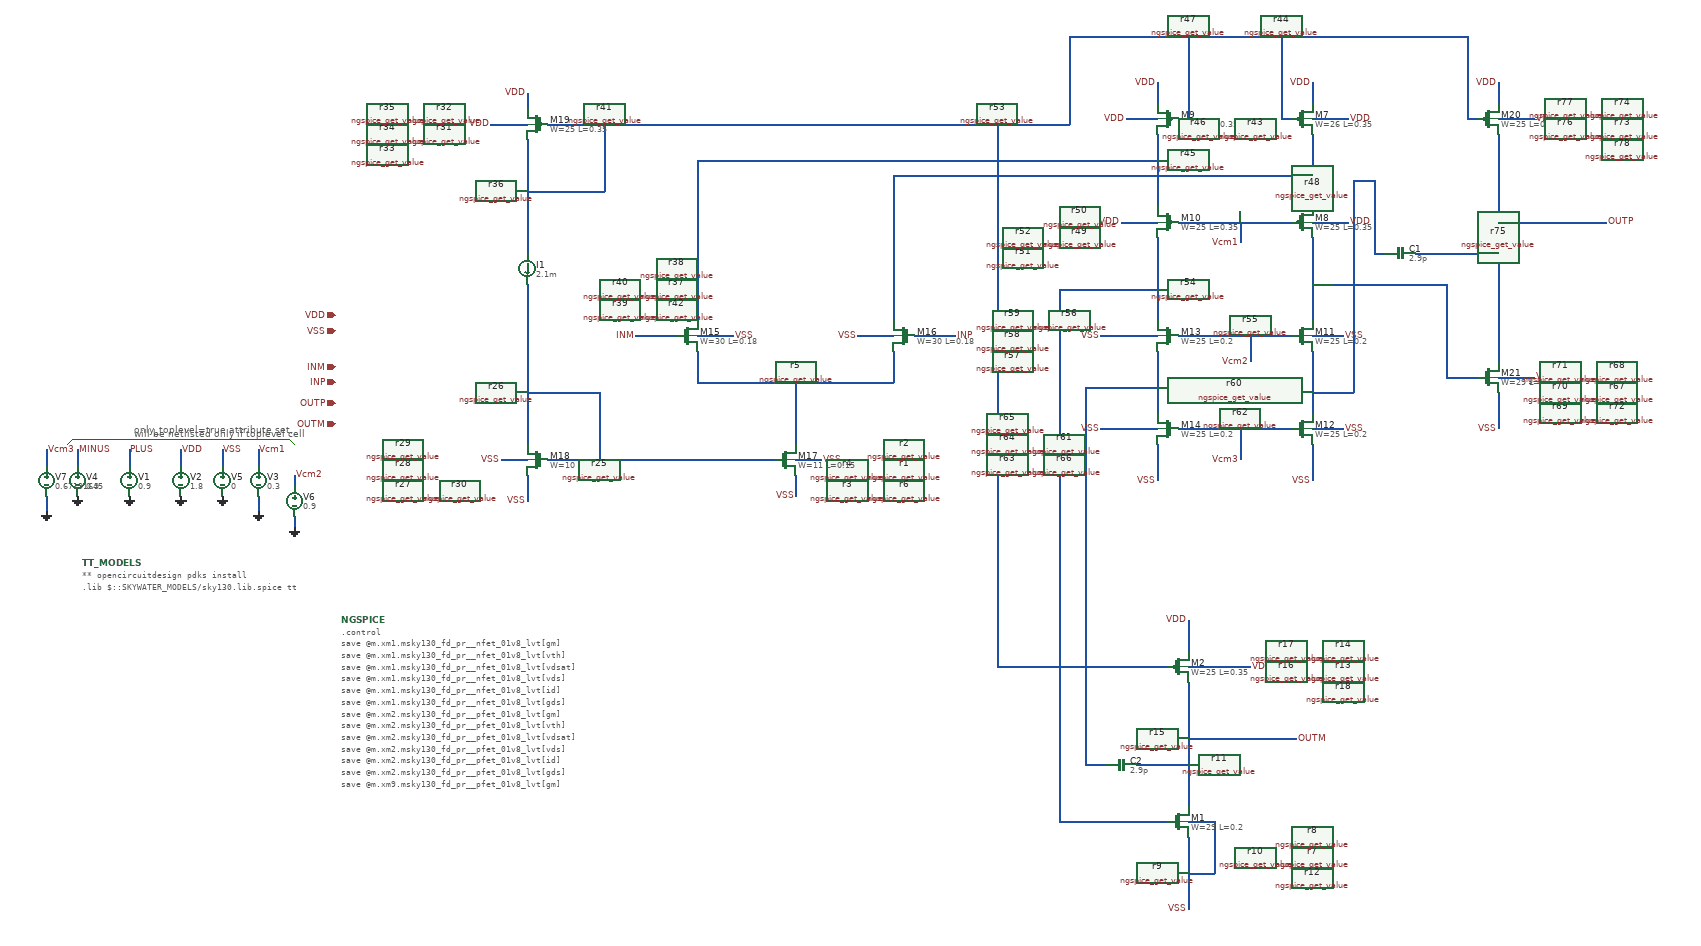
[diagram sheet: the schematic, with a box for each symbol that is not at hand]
v {xschem version=3.0.0 file_version=1.2 }
G {}
K {}
V {}
S {}
E {}
L 4 -460 -200 -90 -200 {}
L 4 -40 -200 -30 -190 {}
L 4 -470 -190 -460 -200 {}
L 4 -90 -200 -40 -200 {}
T {only_toplevel=true attribute set, 
will be netlisted only if toplevel cell} -340 -230 0 0 0.2 0.2 {layer=4}
N -350 -180 -350 -150 { lab=PLUS}
N -450 -180 -450 -150 { lab=MINUS}
N -170 -180 -170 -150 {
lab=VSS}
N -250 -180 -250 -150 {
lab=VDD}
N 1940 -790 1940 -650 {
lab=#net1}
N 1940 -590 1940 -430 {
lab=#net2}
N 1940 -370 1940 -250 {
lab=#net3}
N 1640 -790 1640 -650 {
lab=#net4}
N 1640 -590 1640 -430 {
lab=#net5}
N 1640 -370 1640 -250 {
lab=#net6}
N 750 -370 750 -310 {
lab=#net7}
N 750 -310 1130 -310 {
lab=#net7}
N 1130 -370 1130 -310 {
lab=#net7}
N 940 -310 940 -190 {
lab=#net7}
N 420 -500 420 -190 {
lab=#net8}
N 420 -780 420 -560 {
lab=#net9}
N 750 -740 750 -430 {
lab=#net4}
N 750 -740 1640 -740 {
lab=#net4}
N 1130 -710 1130 -430 {
lab=#net1}
N 1130 -710 1940 -710 {
lab=#net1}
N 1680 -220 1900 -220 {
lab=Vcm3}
N 1680 -400 1900 -400 {
lab=Vcm2}
N 1680 -620 1900 -620 {
lab=Vcm1}
N 2300 -790 2300 -350 {
lab=OUT}
N 2140 -560 2300 -560 {
lab=OUT}
N 2200 -320 2260 -320 {
lab=#net2}
N 2200 -500 2200 -320 {
lab=#net2}
N 1940 -500 2200 -500 {
lab=#net2}
N 460 -160 900 -160 {
lab=#net8}
N 460 -810 1470 -810 {
lab=#net9}
N 1470 -980 1470 -810 {
lab=#net9}
N 1680 -820 1700 -820 {
lab=#net9}
N 1700 -980 1700 -820 {
lab=#net9}
N 1880 -820 1900 -820 {
lab=#net9}
N 1880 -980 1880 -820 {
lab=#net9}
N 2240 -820 2260 -820 {
lab=#net9}
N 2240 -980 2240 -820 {
lab=#net9}
N 420 -130 420 -80 {
lab=VSS}
N 940 -130 940 -90 {
lab=VSS}
N 1640 -190 1640 -120 {
lab=VSS}
N 1940 -190 1940 -120 {
lab=VSS}
N 2300 -290 2300 -220 {
lab=VSS}
N 420 -870 420 -840 {
lab=VDD}
N 1940 -890 1940 -850 {
lab=VDD}
N 2300 -890 2300 -850 {
lab=VDD}
N 1530 -220 1640 -220 {
lab=VSS}
N 1530 -400 1640 -400 {
lab=VSS}
N 2300 -320 2370 -320 {
lab=VSS}
N 1940 -220 2000 -220 {
lab=VSS}
N 1940 -400 2000 -400 {
lab=VSS}
N 2300 -820 2370 -820 {
lab=VDD}
N 1940 -620 2010 -620 {
lab=VDD}
N 1940 -820 2010 -820 {
lab=VDD}
N 1580 -820 1640 -820 {
lab=VDD}
N 1570 -620 1640 -620 {
lab=VDD}
N 1640 -890 1640 -850 {
lab=VDD}
N 1060 -400 1130 -400 {
lab=VSS}
N 750 -400 820 -400 {
lab=VSS}
N 350 -810 420 -810 {
lab=VDD}
N 370 -160 420 -160 {
lab=VSS}
N 940 -160 990 -160 {
lab=VSS}
N 1470 -980 2240 -980 {
lab=#net9}
N 1170 -400 1250 -400 {
lab=PLUS}
N 630 -400 710 -400 {
lab=MINUS}
N 420 -680 570 -680 {
lab=#net9}
N 570 -810 570 -680 {
lab=#net9}
N 1800 -620 1800 -580 {
lab=Vcm1}
N 1820 -400 1820 -350 {
lab=Vcm2}
N 2300 -620 2510 -620 {
lab=OUT}
N -30 -130 -30 -110 {
lab=Vcm2}
N -100 -180 -100 -150 {
lab=Vcm1}
N -100 -90 -100 -60 {
lab=GND}
N -30 -50 -30 -30 {
lab=GND}
N 420 -290 560 -290 {
lab=#net8}
N 560 -290 560 -160 {
lab=#net8}
N 1800 -220 1800 -160 {
lab=Vcm3}
N 1450 -490 1640 -490 {
lab=#net5}
N 1450 -490 1450 140 {
lab=#net5}
N 1330 240 1660 240 {
lab=#net9}
N 1330 -810 1330 240 {
lab=#net9}
N 1700 270 1700 510 {
lab=OUTN}
N 1700 580 1700 710 {
lab=VSS}
N 1700 570 1700 580 {
lab=VSS}
N 1450 540 1660 540 {
lab=#net5}
N 1450 140 1450 540 {
lab=#net5}
N 1700 150 1700 210 {
lab=VDD}
N 1700 240 1820 240 {
lab=VDD}
N 1700 540 1750 540 {
lab=VSS}
N 1750 540 1750 640 {
lab=VSS}
N 1700 640 1750 640 {
lab=VSS}
N 1500 -300 1500 430 {
lab=#net6}
N 1500 430 1540 430 {
lab=#net6}
N 1600 430 1700 430 {
lab=OUTN}
N 1700 380 1910 380 {
lab=OUTN}
N -510 -180 -510 -150 {
lab=Vcm3}
N -510 -90 -510 -60 {
lab=GND}
N 2060 -700 2060 -560 {
lab=#net3}
N 2060 -560 2080 -560 {
lab=#net3}
N 2020 -700 2060 -700 {
lab=#net3}
N 2020 -700 2020 -290 {
lab=#net3}
N 1940 -290 2020 -290 {
lab=#net3}
N 1500 -300 1640 -300 {
lab=#net6}
C {devices/launcher.sym} -210 40 0 0 {name=h1
descr=Backannotate 
tclcommand="ngspice::annotate"}
C {devices/launcher.sym} -210 80 0 0 {name=h2
descr="View Raw file" 
tclcommand="textwindow $netlist_dir/folded_enes.raw"}
C {devices/iopin.sym} 50 -440 0 0 {name=p1 lab=VDD}
C {devices/iopin.sym} 50 -410 0 0 {name=p2 lab=VSS}
C {devices/iopin.sym} 50 -340 0 0 {name=p3 lab=INM}
C {devices/iopin.sym} 50 -310 0 0 {name=p4 lab=INP}
C {devices/iopin.sym} 50 -270 0 0 {name=p5 lab=OUTP}
C {devices/vsource.sym} -350 -120 0 0 {name=V1 value=0.9 only_toplevel=true}
C {devices/gnd.sym} -350 -90 0 0 {name=l10 lab=GND}
C {devices/lab_pin.sym} -350 -180 0 1 {name=l11 sig_type=std_logic lab=PLUS}
C {devices/vsource.sym} -450 -120 0 0 {name=V4 value=0.9 only_toplevel=true}
C {devices/gnd.sym} -450 -90 0 0 {name=l16 lab=GND}
C {devices/lab_pin.sym} -450 -180 0 1 {name=l17 sig_type=std_logic lab=MINUS}
C {devices/vsource.sym} -170 -120 0 0 {name=V5 value=0 only_toplevel=true}
C {devices/gnd.sym} -170 -90 0 0 {name=l18 lab=GND}
C {devices/lab_pin.sym} -170 -180 2 0 {name=l19 sig_type=std_logic lab=VSS}
C {devices/code.sym} -440 40 0 0 {name=TT_MODELS
only_toplevel=true
format="tcleval( @value )"
value="
** opencircuitdesign pdks install
.lib $::SKYWATER_MODELS/sky130.lib.spice tt

"
spice_ignore=false}
C {devices/vsource.sym} -250 -120 0 0 {name=V2 value=1.8 only_toplevel=true}
C {devices/gnd.sym} -250 -90 0 0 {name=l12 lab=GND}
C {devices/lab_pin.sym} -250 -180 2 0 {name=l13 sig_type=std_logic lab=VDD}
C {devices/code_shown.sym} 60 150 0 0 {name=NGSPICE
only_toplevel=true
value="
.control

save @m.xm1.msky130_fd_pr__nfet_01v8_lvt[gm]
save @m.xm1.msky130_fd_pr__nfet_01v8_lvt[vth]
save @m.xm1.msky130_fd_pr__nfet_01v8_lvt[vdsat]
save @m.xm1.msky130_fd_pr__nfet_01v8_lvt[vds]
save @m.xm1.msky130_fd_pr__nfet_01v8_lvt[id]
save @m.xm1.msky130_fd_pr__nfet_01v8_lvt[gds]

save @m.xm2.msky130_fd_pr__pfet_01v8_lvt[gm]
save @m.xm2.msky130_fd_pr__pfet_01v8_lvt[vth]
save @m.xm2.msky130_fd_pr__pfet_01v8_lvt[vdsat]
save @m.xm2.msky130_fd_pr__pfet_01v8_lvt[vds]
save @m.xm2.msky130_fd_pr__pfet_01v8_lvt[id]
save @m.xm2.msky130_fd_pr__pfet_01v8_lvt[gds]

save @m.xm9.msky130_fd_pr__pfet_01v8_lvt[gm]
save @m.xm9.msky130_fd_pr__pfet_01v8_lvt[vth]
save @m.xm9.msky130_fd_pr__pfet_01v8_lvt[vdsat]
save @m.xm9.msky130_fd_pr__pfet_01v8_lvt[vds]
save @m.xm9.msky130_fd_pr__pfet_01v8_lvt[id]
save @m.xm9.msky130_fd_pr__pfet_01v8_lvt[gds]

save @m.xm10.msky130_fd_pr__pfet_01v8_lvt[gm]
save @m.xm10.msky130_fd_pr__pfet_01v8_lvt[vth]
save @m.xm10.msky130_fd_pr__pfet_01v8_lvtv[vdsat]
save @m.xm10.msky130_fd_pr__pfet_01v8_lvt[vds]
save @m.xm10.msky130_fd_pr__pfet_01v8_lvt[id]
save @m.xm10.msky130_fd_pr__pfet_01v8_lvt[gds]

save @m.xm13.msky130_fd_pr__nfet_01v8_lvt[gm]
save @m.xm13.msky130_fd_pr__nfet_01v8_lvt[vth]
save @m.xm13.msky130_fd_pr__nfet_01v8_lvt[vdsat]
save @m.xm13.msky130_fd_pr__nfet_01v8_lvt[vds]
save @m.xm13.msky130_fd_pr__nfet_01v8_lvt[id]
save @m.xm13.msky130_fd_pr__nfet_01v8_lvt[gds]

save @m.xm14.msky130_fd_pr__nfet_01v8_lvt[gm]
save @m.xm14.msky130_fd_pr__nfet_01v8_lvt[vth]
save @m.xm14.msky130_fd_pr__nfet_01v8_lvt[vdsat]
save @m.xm14.msky130_fd_pr__nfet_01v8_lvt[vds]
save @m.xm14.msky130_fd_pr__nfet_01v8_lvt[id]
save @m.xm14.msky130_fd_pr__nfet_01v8_lvt[gds]

save @m.xm15.msky130_fd_pr__nfet_01v8_lvt[gm]
save @m.xm15.msky130_fd_pr__nfet_01v8_lvt[vth]
save @m.xm15.msky130_fd_pr__nfet_01v8_lvt[vdsat]
save @m.xm15.msky130_fd_pr__nfet_01v8_lvt[vds]
save @m.xm15.msky130_fd_pr__nfet_01v8_lvt[id]
save @m.xm15.msky130_fd_pr__nfet_01v8_lvt[gds]

save @m.xm17.msky130_fd_pr__nfet_01v8_lvt[gm]
save @m.xm17.msky130_fd_pr__nfet_01v8_lvt[vth]
save @m.xm17.msky130_fd_pr__nfet_01v8_lvt[vdsat]
save @m.xm17.msky130_fd_pr__nfet_01v8_lvt[vds]
save @m.xm17.msky130_fd_pr__nfet_01v8_lvt[id]
save @m.xm17.msky130_fd_pr__nfet_01v8_lvt[gds]

save @m.xm18.msky130_fd_pr__nfet_01v8[gm]
save @m.xm18.msky130_fd_pr__nfet_01v8[vth]
save @m.xm18.msky130_fd_pr__nfet_01v8[vdsat]
save @m.xm18.msky130_fd_pr__nfet_01v8[vds]
save @m.xm18.msky130_fd_pr__nfet_01v8[id]
save @m.xm18.msky130_fd_pr__nfet_01v8[gds]

save @m.xm19.msky130_fd_pr__pfet_01v8_lvt[gm]
save @m.xm19.msky130_fd_pr__pfet_01v8_lvt[vth]
save @m.xm19.msky130_fd_pr__pfet_01v8_lvt[vdsat]
save @m.xm19.msky130_fd_pr__pfet_01v8_lvt[vds]
save @m.xm19.msky130_fd_pr__pfet_01v8_lvt[id]
save @m.xm19.msky130_fd_pr__pfet_01v8_lvt[gds]

save @m.xm20.msky130_fd_pr__pfet_01v8_lvt[gm]
save @m.xm20.msky130_fd_pr__pfet_01v8_lvt[vth]
save @m.xm20.msky130_fd_pr__pfet_01v8_lvt[vdsat]
save @m.xm20.msky130_fd_pr__pfet_01v8_lvt[vds]
save @m.xm20.msky130_fd_pr__pfet_01v8_lvt[id]
save @m.xm20.msky130_fd_pr__pfet_01v8_lvt[gds]

save @m.xm21.msky130_fd_pr__nfet_01v8_lvt[gm]
save @m.xm21.msky130_fd_pr__nfet_01v8_lvt[vth]
save @m.xm21.msky130_fd_pr__nfet_01v8_lvt[vdsat]
save @m.xm21.msky130_fd_pr__nfet_01v8_lvt[vds]
save @m.xm21.msky130_fd_pr__nfet_01v8_lvt[id]
save @m.xm21.msky130_fd_pr__nfet_01v8_lvt[gds]

save all

op
write folded_enes_fd.raw
.dc Vcm3 Gnd 0.68 0.7 0.002


.endc
"}
C {sky130_fd_pr/pfet_01v8_lvt.sym} 1920 -820 0 0 {name=M7
L=0.35
W=26
nf=1
mult=3
ad="'int((nf+1)/2) * W/nf * 0.29'" 
pd="'2*int((nf+1)/2) * (W/nf + 0.29)'"
as="'int((nf+2)/2) * W/nf * 0.29'" 
ps="'2*int((nf+2)/2) * (W/nf + 0.29)'"
nrd="'0.29 / W'" nrs="'0.29 / W'"
sa=0 sb=0 sd=0
model=pfet_01v8_lvt
spiceprefix=X
}
C {sky130_fd_pr/pfet_01v8_lvt.sym} 1920 -620 0 0 {name=M8
L=0.35
W=25
nf=1
mult=3
ad="'int((nf+1)/2) * W/nf * 0.29'" 
pd="'2*int((nf+1)/2) * (W/nf + 0.29)'"
as="'int((nf+2)/2) * W/nf * 0.29'" 
ps="'2*int((nf+2)/2) * (W/nf + 0.29)'"
nrd="'0.29 / W'" nrs="'0.29 / W'"
sa=0 sb=0 sd=0
model=pfet_01v8_lvt
spiceprefix=X
}
C {sky130_fd_pr/pfet_01v8_lvt.sym} 1660 -820 0 1 {name=M9
L=0.35
W=26
nf=1
mult=3
ad="'int((nf+1)/2) * W/nf * 0.29'" 
pd="'2*int((nf+1)/2) * (W/nf + 0.29)'"
as="'int((nf+2)/2) * W/nf * 0.29'" 
ps="'2*int((nf+2)/2) * (W/nf + 0.29)'"
nrd="'0.29 / W'" nrs="'0.29 / W'"
sa=0 sb=0 sd=0
model=pfet_01v8_lvt
spiceprefix=X
}
C {sky130_fd_pr/pfet_01v8_lvt.sym} 1660 -620 0 1 {name=M10
L=0.35
W=25
nf=1
mult=3
ad="'int((nf+1)/2) * W/nf * 0.29'" 
pd="'2*int((nf+1)/2) * (W/nf + 0.29)'"
as="'int((nf+2)/2) * W/nf * 0.29'" 
ps="'2*int((nf+2)/2) * (W/nf + 0.29)'"
nrd="'0.29 / W'" nrs="'0.29 / W'"
sa=0 sb=0 sd=0
model=pfet_01v8_lvt
spiceprefix=X
}
C {sky130_fd_pr/nfet_01v8_lvt.sym} 1920 -400 0 0 {name=M11
L=0.2
W=25
nf=1
mult=4
ad="'int((nf+1)/2) * W/nf * 0.29'" 
pd="'2*int((nf+1)/2) * (W/nf + 0.29)'"
as="'int((nf+2)/2) * W/nf * 0.29'" 
ps="'2*int((nf+2)/2) * (W/nf + 0.29)'"
nrd="'0.29 / W'" nrs="'0.29 / W'"
sa=0 sb=0 sd=0
model=nfet_01v8_lvt
spiceprefix=X
}
C {sky130_fd_pr/nfet_01v8_lvt.sym} 1920 -220 0 0 {name=M12
L=0.2
W=25
nf=1
mult=4
ad="'int((nf+1)/2) * W/nf * 0.29'" 
pd="'2*int((nf+1)/2) * (W/nf + 0.29)'"
as="'int((nf+2)/2) * W/nf * 0.29'" 
ps="'2*int((nf+2)/2) * (W/nf + 0.29)'"
nrd="'0.29 / W'" nrs="'0.29 / W'"
sa=0 sb=0 sd=0
model=nfet_01v8_lvt
spiceprefix=X
}
C {sky130_fd_pr/nfet_01v8_lvt.sym} 1660 -400 0 1 {name=M13
L=0.2
W=25
nf=1
mult=4
ad="'int((nf+1)/2) * W/nf * 0.29'" 
pd="'2*int((nf+1)/2) * (W/nf + 0.29)'"
as="'int((nf+2)/2) * W/nf * 0.29'" 
ps="'2*int((nf+2)/2) * (W/nf + 0.29)'"
nrd="'0.29 / W'" nrs="'0.29 / W'"
sa=0 sb=0 sd=0
model=nfet_01v8_lvt
spiceprefix=X
}
C {sky130_fd_pr/nfet_01v8_lvt.sym} 1660 -220 0 1 {name=M14
L=0.2
W=25
nf=1
mult=4
ad="'int((nf+1)/2) * W/nf * 0.29'" 
pd="'2*int((nf+1)/2) * (W/nf + 0.29)'"
as="'int((nf+2)/2) * W/nf * 0.29'" 
ps="'2*int((nf+2)/2) * (W/nf + 0.29)'"
nrd="'0.29 / W'" nrs="'0.29 / W'"
sa=0 sb=0 sd=0
model=nfet_01v8_lvt
spiceprefix=X
}
C {sky130_fd_pr/nfet_01v8_lvt.sym} 730 -400 0 0 {name=M15
L=0.18
W=30
nf=1
mult=5
ad="'int((nf+1)/2) * W/nf * 0.29'" 
pd="'2*int((nf+1)/2) * (W/nf + 0.29)'"
as="'int((nf+2)/2) * W/nf * 0.29'" 
ps="'2*int((nf+2)/2) * (W/nf + 0.29)'"
nrd="'0.29 / W'" nrs="'0.29 / W'"
sa=0 sb=0 sd=0
model=nfet_01v8_lvt
spiceprefix=X
}
C {sky130_fd_pr/nfet_01v8_lvt.sym} 1150 -400 0 1 {name=M16
L=0.18
W=30
nf=1
mult=5
ad="'int((nf+1)/2) * W/nf * 0.29'" 
pd="'2*int((nf+1)/2) * (W/nf + 0.29)'"
as="'int((nf+2)/2) * W/nf * 0.29'" 
ps="'2*int((nf+2)/2) * (W/nf + 0.29)'"
nrd="'0.29 / W'" nrs="'0.29 / W'"
sa=0 sb=0 sd=0
model=nfet_01v8_lvt
spiceprefix=X
}
C {sky130_fd_pr/nfet_01v8.sym} 440 -160 0 1 {name=M18
L=0.15
W=10
nf=1
mult=5
ad="'int((nf+1)/2) * W/nf * 0.29'" 
pd="'2*int((nf+1)/2) * (W/nf + 0.29)'"
as="'int((nf+2)/2) * W/nf * 0.29'" 
ps="'2*int((nf+2)/2) * (W/nf + 0.29)'"
nrd="'0.29 / W'" nrs="'0.29 / W'"
sa=0 sb=0 sd=0
model=nfet_01v8
spiceprefix=X
}
C {devices/isource.sym} 420 -530 0 0 {name=I1 value=2.1m only_toplevel=false}
C {sky130_fd_pr/pfet_01v8_lvt.sym} 440 -810 0 1 {name=M19
L=0.35
W=25
nf=1
mult=3
ad="'int((nf+1)/2) * W/nf * 0.29'" 
pd="'2*int((nf+1)/2) * (W/nf + 0.29)'"
as="'int((nf+2)/2) * W/nf * 0.29'" 
ps="'2*int((nf+2)/2) * (W/nf + 0.29)'"
nrd="'0.29 / W'" nrs="'0.29 / W'"
sa=0 sb=0 sd=0
model=pfet_01v8_lvt
spiceprefix=X
}
C {sky130_fd_pr/pfet_01v8_lvt.sym} 2280 -820 0 0 {name=M20
L=0.35
W=25
nf=1
mult=5
ad="'int((nf+1)/2) * W/nf * 0.29'" 
pd="'2*int((nf+1)/2) * (W/nf + 0.29)'"
as="'int((nf+2)/2) * W/nf * 0.29'" 
ps="'2*int((nf+2)/2) * (W/nf + 0.29)'"
nrd="'0.29 / W'" nrs="'0.29 / W'"
sa=0 sb=0 sd=0
model=pfet_01v8_lvt
spiceprefix=X
}
C {sky130_fd_pr/nfet_01v8_lvt.sym} 2280 -320 0 0 {name=M21
L=0.2
W=29
nf=1
mult=11
ad="'int((nf+1)/2) * W/nf * 0.29'" 
pd="'2*int((nf+1)/2) * (W/nf + 0.29)'"
as="'int((nf+2)/2) * W/nf * 0.29'" 
ps="'2*int((nf+2)/2) * (W/nf + 0.29)'"
nrd="'0.29 / W'" nrs="'0.29 / W'"
sa=0 sb=0 sd=0
model=nfet_01v8_lvt
spiceprefix=X
}
C {devices/capa.sym} 2110 -560 1 0 {name=C1
m=1
value=2.9p
footprint=1206
device="ceramic capacitor"}
C {devices/lab_pin.sym} 420 -80 3 0 {name=l14 sig_type=std_logic lab=VSS}
C {devices/lab_pin.sym} 940 -90 3 0 {name=l15 sig_type=std_logic lab=VSS}
C {devices/lab_pin.sym} 1640 -120 3 0 {name=l22 sig_type=std_logic lab=VSS}
C {devices/lab_pin.sym} 1940 -120 3 0 {name=l23 sig_type=std_logic lab=VSS}
C {devices/lab_pin.sym} 2300 -220 3 0 {name=l24 sig_type=std_logic lab=VSS}
C {devices/lab_pin.sym} 420 -870 1 0 {name=l25 sig_type=std_logic lab=VDD}
C {devices/lab_pin.sym} 1640 -890 1 0 {name=l26 sig_type=std_logic lab=VDD}
C {devices/lab_pin.sym} 1940 -890 1 0 {name=l27 sig_type=std_logic lab=VDD}
C {devices/lab_pin.sym} 2300 -890 1 0 {name=l28 sig_type=std_logic lab=VDD}
C {devices/lab_pin.sym} 1530 -220 0 0 {name=l29 sig_type=std_logic lab=VSS}
C {devices/lab_pin.sym} 1530 -400 0 0 {name=l30 sig_type=std_logic lab=VSS}
C {devices/lab_pin.sym} 2000 -400 0 1 {name=l31 sig_type=std_logic lab=VSS}
C {devices/lab_pin.sym} 2000 -220 0 1 {name=l32 sig_type=std_logic lab=VSS}
C {devices/lab_pin.sym} 2370 -320 0 1 {name=l33 sig_type=std_logic lab=VSS}
C {devices/lab_pin.sym} 2370 -820 2 0 {name=l34 sig_type=std_logic lab=VDD}
C {devices/lab_pin.sym} 2010 -820 2 0 {name=l35 sig_type=std_logic lab=VDD}
C {devices/lab_pin.sym} 1580 -820 2 1 {name=l36 sig_type=std_logic lab=VDD}
C {devices/lab_pin.sym} 2010 -620 2 0 {name=l37 sig_type=std_logic lab=VDD}
C {devices/lab_pin.sym} 1570 -620 2 1 {name=l38 sig_type=std_logic lab=VDD}
C {devices/lab_pin.sym} 350 -810 2 1 {name=l39 sig_type=std_logic lab=VDD}
C {devices/lab_pin.sym} 1060 -400 0 0 {name=l40 sig_type=std_logic lab=VSS}
C {devices/lab_pin.sym} 820 -400 0 1 {name=l41 sig_type=std_logic lab=VSS}
C {devices/lab_pin.sym} 370 -160 0 0 {name=l42 sig_type=std_logic lab=VSS}
C {devices/lab_pin.sym} 990 -160 0 1 {name=l43 sig_type=std_logic lab=VSS}
C {devices/lab_pin.sym} 1250 -400 0 1 {name=l44 sig_type=std_logic lab=INP}
C {devices/lab_pin.sym} 630 -400 0 0 {name=l45 sig_type=std_logic lab=INM}
C {devices/lab_pin.sym} 1800 -580 3 0 {name=l46 sig_type=std_logic lab=Vcm1}
C {devices/lab_pin.sym} 1820 -350 3 0 {name=l47 sig_type=std_logic lab=Vcm2}
C {devices/spice_probe.sym} 2300 -560 0 0 {name=p11 attrs=""
voltage=0.9077}
C {devices/spice_probe.sym} 1800 -620 0 0 {name=p12 attrs=""
voltage=0.3}
C {devices/spice_probe.sym} 1820 -400 0 0 {name=p13 attrs=""
voltage=0.9}
C {devices/spice_probe.sym} 1640 -510 0 0 {name=p14 attrs=""
voltage=0.6719}
C {devices/spice_probe.sym} 570 -810 0 0 {name=p15 attrs=""
voltage=0.9086}
C {devices/spice_probe.sym} 1640 -740 0 0 {name=p16 attrs=""
voltage=1.094}
C {devices/spice_probe.sym} 1940 -710 0 0 {name=p17 attrs=""
voltage=1.094}
C {devices/spice_probe.sym} 940 -310 0 0 {name=p18 attrs=""
voltage=0.2122}
C {devices/spice_probe.sym} 420 -320 0 0 {name=p19 attrs=""
voltage=0.8715}
C {devices/ngspice_get_value.sym} 290 -140 0 0 {name=r25 node=@m.xm18.msky130_fd_pr__nfet_01v8[gm]
descr="gm="}
C {devices/ngspice_get_value.sym} 290 -180 0 0 {name=r26 node="i(@m.xm18.msky130_fd_pr__nfet_01v8[id])"
descr="Id="}
C {devices/ngspice_get_value.sym} 180 -100 0 0 {name=r27 node="v(@m.xm18.msky130_fd_pr__nfet_01v8[vth])"
descr="Vth="}
C {devices/ngspice_get_value.sym} 180 -140 0 0 {name=r28 node="v(@m.xm18.msky130_fd_pr__nfet_01v8[vdsat])"
descr="Vdsat="}
C {devices/ngspice_get_value.sym} 180 -180 0 0 {name=r29 node="v(@m.xm18.msky130_fd_pr__nfet_01v8[vds])"
descr="Vds="}
C {devices/ngspice_get_value.sym} 290 -100 0 0 {name=r30 node="@m.xm18.msky130_fd_pr__nfet_01v8[gds]"
descr="gds="}
C {devices/ngspice_get_value.sym} 260 -790 0 0 {name=r31 node=@m.xm19.msky130_fd_pr__pfet_01v8_lvt[gm]
descr="gm="}
C {devices/ngspice_get_value.sym} 260 -830 0 0 {name=r32 node="i(@m.xm19.msky130_fd_pr__pfet_01v8_lvt[id])"
descr="Id="}
C {devices/ngspice_get_value.sym} 150 -750 0 0 {name=r33 node="v(@m.xm19.msky130_fd_pr__pfet_01v8_lvt[vth])"
descr="Vth="}
C {devices/ngspice_get_value.sym} 150 -790 0 0 {name=r34 node="v(@m.xm19.msky130_fd_pr__pfet_01v8_lvt[vdsat])"
descr="Vdsat="}
C {devices/ngspice_get_value.sym} 150 -830 0 0 {name=r35 node="v(@m.xm19.msky130_fd_pr__pfet_01v8_lvt[vds])"
descr="Vds="}
C {devices/ngspice_get_value.sym} 260 -750 0 0 {name=r36 node="@m.xm19.msky130_fd_pr__pfet_01v8_lvt[gds]"
descr="gds="}
C {devices/ngspice_get_value.sym} 710 -490 0 0 {name=r37 node=@m.xm15.msky130_fd_pr__nfet_01v8_lvt[gm]
descr="gm="}
C {devices/ngspice_get_value.sym} 710 -530 0 0 {name=r38 node="i(@m.xm15.msky130_fd_pr__nfet_01v8_lvt[id])"
descr="Id="}
C {devices/ngspice_get_value.sym} 600 -450 0 0 {name=r39 node="v(@m.xm15.msky130_fd_pr__nfet_01v8_lvt[vth])"
descr="Vth="}
C {devices/ngspice_get_value.sym} 600 -490 0 0 {name=r40 node="v(@m.xm15.msky130_fd_pr__nfet_01v8_lvt[vdsat])"
descr="Vdsat="}
C {devices/ngspice_get_value.sym} 600 -530 0 0 {name=r41 node="v(@m.xm15.msky130_fd_pr__nfet_01v8_lvt[vds])"
descr="Vds="}
C {devices/ngspice_get_value.sym} 710 -450 0 0 {name=r42 node="@m.xm15.msky130_fd_pr__nfet_01v8_lvt[gds]"
descr="gds="}
C {devices/ngspice_get_value.sym} 1830 -800 0 0 {name=r43 node=@m.xm9.msky130_fd_pr__pfet_01v8_lvt[gm]
descr="gm="}
C {devices/ngspice_get_value.sym} 1830 -840 0 0 {name=r44 node="i(@m.xm9.msky130_fd_pr__pfet_01v8_lvt[id])"
descr="Id="}
C {devices/ngspice_get_value.sym} 1720 -760 0 0 {name=r45 node="v(@m.xm9.msky130_fd_pr__pfet_01v8_lvt[vth])"
descr="Vth="}
C {devices/ngspice_get_value.sym} 1720 -800 0 0 {name=r46 node="v(@m.xm9.msky130_fd_pr__pfet_01v8_lvt[vdsat])"
descr="Vdsat="}
C {devices/ngspice_get_value.sym} 1720 -840 0 0 {name=r47 node="v(@m.xm9.msky130_fd_pr__pfet_01v8_lvt[vds])"
descr="Vds="}
C {devices/ngspice_get_value.sym} 1830 -760 0 0 {name=r48 node="@m.xm9.msky130_fd_pr__pfet_01v8_lvt[gds]"
descr="gds="}
C {devices/ngspice_get_value.sym} 1490 -590 0 0 {name=r49 node=@m.xm10.msky130_fd_pr__pfet_01v8_lvt[gm]
descr="gm="}
C {devices/ngspice_get_value.sym} 1490 -630 0 0 {name=r50 node="i(@m.xm10.msky130_fd_pr__pfet_01v8_lvt[id])"
descr="Id="}
C {devices/ngspice_get_value.sym} 1380 -550 0 0 {name=r51 node="v(@m.xm10.msky130_fd_pr__pfet_01v8_lvt[vth])"
descr="Vth="}
C {devices/ngspice_get_value.sym} 1380 -590 0 0 {name=r52 node="v(@m.xm10.msky130_fd_pr__pfet_01v8_lvt[vdsat])"
descr="Vdsat="}
C {devices/ngspice_get_value.sym} 1380 -630 0 0 {name=r53 node="v(@m.xm10.msky130_fd_pr__pfet_01v8_lvt[vds])"
descr="Vds="}
C {devices/ngspice_get_value.sym} 1490 -550 0 0 {name=r54 node="@m.xm10.msky130_fd_pr__pfet_01v8_lvt[gds]"
descr="gds="}
C {devices/ngspice_get_value.sym} 1470 -390 0 0 {name=r55 node=@m.xm13.msky130_fd_pr__nfet_01v8_lvt[gm]
descr="gm="}
C {devices/ngspice_get_value.sym} 1470 -430 0 0 {name=r56 node="i(@m.xm13.msky130_fd_pr__nfet_01v8_lvt[id])"
descr="Id="}
C {devices/ngspice_get_value.sym} 1360 -350 0 0 {name=r57 node="v(@m.xm13.msky130_fd_pr__nfet_01v8_lvt[vth])"
descr="Vth="}
C {devices/ngspice_get_value.sym} 1360 -390 0 0 {name=r58 node="v(@m.xm13.msky130_fd_pr__nfet_01v8_lvt[vdsat])"
descr="Vdsat="}
C {devices/ngspice_get_value.sym} 1360 -430 0 0 {name=r59 node="v(@m.xm13.msky130_fd_pr__nfet_01v8_lvt[vds])"
descr="Vds="}
C {devices/ngspice_get_value.sym} 1470 -350 0 0 {name=r60 node="@m.xm13.msky130_fd_pr__nfet_01v8_lvt[gds]"
descr="gds="}
C {devices/ngspice_get_value.sym} 1460 -190 0 0 {name=r61 node=@m.xm14.msky130_fd_pr__nfet_01v8_lvt[gm]
descr="gm="}
C {devices/ngspice_get_value.sym} 1460 -230 0 0 {name=r62 node="i(@m.xm14.msky130_fd_pr__nfet_01v8_lvt[id])"
descr="Id="}
C {devices/ngspice_get_value.sym} 1350 -150 0 0 {name=r63 node="v(@m.xm14.msky130_fd_pr__nfet_01v8_lvt[vth])"
descr="Vth="}
C {devices/ngspice_get_value.sym} 1350 -190 0 0 {name=r64 node="v(@m.xm14.msky130_fd_pr__nfet_01v8_lvt[vdsat])"
descr="Vdsat="}
C {devices/ngspice_get_value.sym} 1350 -230 0 0 {name=r65 node="v(@m.xm14.msky130_fd_pr__nfet_01v8_lvt[vds])"
descr="Vds="}
C {devices/ngspice_get_value.sym} 1460 -150 0 0 {name=r66 node="@m.xm14.msky130_fd_pr__nfet_01v8_lvt[gds]"
descr="gds="}
C {devices/ngspice_get_value.sym} 2530 -290 0 0 {name=r67 node=@m.xm21.msky130_fd_pr__nfet_01v8_lvt[gm]
descr="gm="}
C {devices/ngspice_get_value.sym} 2530 -330 0 0 {name=r68 node="i(@m.xm21.msky130_fd_pr__nfet_01v8_lvt[id])"
descr="Id="}
C {devices/ngspice_get_value.sym} 2420 -250 0 0 {name=r69 node="v(@m.xm21.msky130_fd_pr__nfet_01v8_lvt[vth])"
descr="Vth="}
C {devices/ngspice_get_value.sym} 2420 -290 0 0 {name=r70 node="v(@m.xm21.msky130_fd_pr__nfet_01v8_lvt[vdsat])"
descr="Vdsat="}
C {devices/ngspice_get_value.sym} 2420 -330 0 0 {name=r71 node="v(@m.xm21.msky130_fd_pr__nfet_01v8_lvt[vds])"
descr="Vds="}
C {devices/ngspice_get_value.sym} 2530 -250 0 0 {name=r72 node="@m.xm21.msky130_fd_pr__nfet_01v8_lvt[gds]"
descr="gds="}
C {devices/ngspice_get_value.sym} 2540 -800 0 0 {name=r73 node=@m.xm20.msky130_fd_pr__pfet_01v8_lvt[gm]
descr="gm="}
C {devices/ngspice_get_value.sym} 2540 -840 0 0 {name=r74 node="i(@m.xm20.msky130_fd_pr__pfet_01v8_lvt[id])"
descr="Id="}
C {devices/ngspice_get_value.sym} 2430 -760 0 0 {name=r75 node="v(@m.xm20.msky130_fd_pr__pfet_01v8_lvt[vth])"
descr="Vth="}
C {devices/ngspice_get_value.sym} 2430 -800 0 0 {name=r76 node="v(@m.xm20.msky130_fd_pr__pfet_01v8_lvt[vdsat])"
descr="Vdsat="}
C {devices/ngspice_get_value.sym} 2430 -840 0 0 {name=r77 node="v(@m.xm20.msky130_fd_pr__pfet_01v8_lvt[vds])"
descr="Vds="}
C {devices/ngspice_get_value.sym} 2540 -760 0 0 {name=r78 node="@m.xm20.msky130_fd_pr__pfet_01v8_lvt[gds]"
descr="gds="}
C {devices/spice_probe.sym} 1800 -980 0 0 {name=p20 attrs=""
voltage=0.9086}
C {devices/lab_pin.sym} 2510 -620 2 0 {name=l48 sig_type=std_logic lab=OUTP}
C {devices/vsource.sym} -100 -120 0 0 {name=V3 value=0.3 only_toplevel=false}
C {devices/vsource.sym} -30 -80 0 0 {name=V6 value=0.9 only_toplevel=false}
C {devices/lab_pin.sym} -100 -180 2 0 {name=l1 sig_type=std_logic lab=Vcm1}
C {devices/lab_pin.sym} -30 -130 2 0 {name=l2 sig_type=std_logic lab=Vcm2}
C {devices/gnd.sym} -100 -60 0 0 {name=l3 lab=GND}
C {devices/gnd.sym} -30 -30 0 0 {name=l4 lab=GND}
C {devices/spice_probe.sym} 1640 -300 0 0 {name=p6 attrs=""
voltage=0.2081}
C {devices/spice_probe.sym} 1940 -310 0 0 {name=p7 attrs=""
voltage=0.2081}
C {devices/ngspice_get_value.sym} 1150 -140 0 0 {name=r1 node=@m.xm17.msky130_fd_pr__nfet_01v8_lvt[gm]
descr="gm="}
C {devices/ngspice_get_value.sym} 1150 -180 0 0 {name=r2 node="i(@m.xm17.msky130_fd_pr__nfet_01v8_lvt[id])"
descr="Id="}
C {devices/ngspice_get_value.sym} 1040 -100 0 0 {name=r3 node="v(@m.xm17.msky130_fd_pr__nfet_01v8_lvt[vth])"
descr="Vth="}
C {devices/ngspice_get_value.sym} 1040 -140 0 0 {name=r4 node="v(@m.xm17.msky130_fd_pr__nfet_01v8_lvt[vdsat])"
descr="Vdsat="}
C {devices/ngspice_get_value.sym} 1040 -180 0 0 {name=r5 node="v(@m.xm17.msky130_fd_pr__nfet_01v8_lvt[vds])"
descr="Vds="}
C {devices/ngspice_get_value.sym} 1150 -100 0 0 {name=r6 node="@m.xm17.msky130_fd_pr__nfet_01v8_lvt[gds]"
descr="gds="}
C {sky130_fd_pr/nfet_01v8_lvt.sym} 1680 540 0 0 {name=M1
L=0.2
W=29
nf=1
mult=11
ad="'int((nf+1)/2) * W/nf * 0.29'" 
pd="'2*int((nf+1)/2) * (W/nf + 0.29)'"
as="'int((nf+2)/2) * W/nf * 0.29'" 
ps="'2*int((nf+2)/2) * (W/nf + 0.29)'"
nrd="'0.29 / W'" nrs="'0.29 / W'"
sa=0 sb=0 sd=0
model=nfet_01v8_lvt
spiceprefix=X
}
C {sky130_fd_pr/pfet_01v8_lvt.sym} 1680 240 0 0 {name=M2
L=0.35
W=25
nf=1
mult=5
ad="'int((nf+1)/2) * W/nf * 0.29'" 
pd="'2*int((nf+1)/2) * (W/nf + 0.29)'"
as="'int((nf+2)/2) * W/nf * 0.29'" 
ps="'2*int((nf+2)/2) * (W/nf + 0.29)'"
nrd="'0.29 / W'" nrs="'0.29 / W'"
sa=0 sb=0 sd=0
model=pfet_01v8_lvt
spiceprefix=X
}
C {devices/lab_pin.sym} 1700 150 1 0 {name=l5 sig_type=std_logic lab=VDD}
C {devices/lab_pin.sym} 1820 240 2 0 {name=l6 sig_type=std_logic lab=VDD}
C {devices/lab_pin.sym} 1700 710 3 0 {name=l7 sig_type=std_logic lab=VSS}
C {devices/capa.sym} 1570 430 1 0 {name=C2
m=1
value=2.9p
footprint=1206
device="ceramic capacitor"}
C {devices/lab_pin.sym} 1800 -160 3 0 {name=l8 sig_type=std_logic lab=Vcm3}
C {devices/lab_pin.sym} 1910 380 2 0 {name=l9 sig_type=std_logic lab=OUTM}
C {devices/iopin.sym} 50 -230 0 0 {name=p8 lab=OUTM}
C {devices/ngspice_get_value.sym} 1940 610 0 0 {name=r7 node=@m.xm1.msky130_fd_pr__nfet_01v8_lvt[gm]
descr="gm="}
C {devices/ngspice_get_value.sym} 1940 570 0 0 {name=r8 node="i(@m.xm1.msky130_fd_pr__nfet_01v8_lvt[id])"
descr="Id="}
C {devices/ngspice_get_value.sym} 1830 650 0 0 {name=r9 node="v(@m.xm1.msky130_fd_pr__nfet_01v8_lvt[vth])"
descr="Vth="}
C {devices/ngspice_get_value.sym} 1830 610 0 0 {name=r10 node="v(@m.xm1.msky130_fd_pr__nfet_01v8_lvt[vdsat])"
descr="Vdsat="}
C {devices/ngspice_get_value.sym} 1830 570 0 0 {name=r11 node="v(@m.xm1.msky130_fd_pr__nfet_01v8_lvt[vds])"
descr="Vds="}
C {devices/ngspice_get_value.sym} 1940 650 0 0 {name=r12 node="@m.xm1.msky130_fd_pr__nfet_01v8_lvt[gds]"
descr="gds="}
C {devices/ngspice_get_value.sym} 2000 250 0 0 {name=r13 node=@m.xm2.msky130_fd_pr__pfet_01v8_lvt[gm]
descr="gm="}
C {devices/ngspice_get_value.sym} 2000 210 0 0 {name=r14 node="i(@m.xm2.msky130_fd_pr__pfet_01v8_lvt[id])"
descr="Id="}
C {devices/ngspice_get_value.sym} 1890 290 0 0 {name=r15 node="v(@m.xm2.msky130_fd_pr__pfet_01v8_lvt[vth])"
descr="Vth="}
C {devices/ngspice_get_value.sym} 1890 250 0 0 {name=r16 node="v(@m.xm2.msky130_fd_pr__pfet_01v8_lvt[vdsat])"
descr="Vdsat="}
C {devices/ngspice_get_value.sym} 1890 210 0 0 {name=r17 node="v(@m.xm2.msky130_fd_pr__pfet_01v8_lvt[vds])"
descr="Vds="}
C {devices/ngspice_get_value.sym} 2000 290 0 0 {name=r18 node="@m.xm2.msky130_fd_pr__pfet_01v8_lvt[gds]"
descr="gds="}
C {devices/vsource.sym} -510 -120 0 0 {name=V7 value=0.67191645 only_toplevel=false}
C {devices/gnd.sym} -510 -60 0 0 {name=l20 lab=GND}
C {devices/lab_pin.sym} -510 -180 2 0 {name=l21 sig_type=std_logic lab=Vcm3}
C {devices/spice_probe.sym} 1800 -220 0 0 {name=p9 attrs=""
voltage=0.6719}
C {devices/spice_probe.sym} 1700 380 0 0 {name=p10 attrs=""
voltage=0.9077}
C {devices/spice_probe.sym} 1370 240 0 0 {name=p21 attrs=""
voltage=0.9086}
C {devices/spice_probe.sym} 1500 130 0 0 {name=p22 attrs=""
voltage=0.2081}
C {sky130_fd_pr/nfet3_01v8_lvt.sym} 920 -160 0 0 {name=M17
L=0.15
W=11
nf=1
mult=4
body=GND
ad="'int((nf+1)/2) * W/nf * 0.29'" 
pd="'2*int((nf+1)/2) * (W/nf + 0.29)'"
as="'int((nf+2)/2) * W/nf * 0.29'" 
ps="'2*int((nf+2)/2) * (W/nf + 0.29)'"
nrd="'0.29 / W'" nrs="'0.29 / W'"
sa=0 sb=0 sd=0
model=nfet_01v8_lvt
spiceprefix=X
}
C {devices/spice_probe.sym} 1940 -500 0 0 {name=p23 attrs=""
voltage=0.6719}
